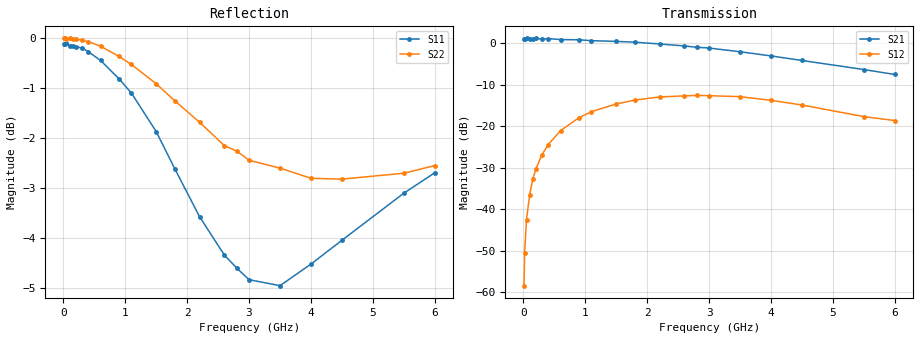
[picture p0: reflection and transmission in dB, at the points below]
! SIEMENS Small Signal Semiconductors
! BFP181
! Si NPN RF Bipolar Junction Transistor in SOT143
! VCE = 1.75 V  IC = 0.3 mA
! Common Emitter S-Parameters:  March  1996
# GHz  S  MA  R  50
!  f  S11  S21  S12  S22
! GHz  MAG  ANG  MAG  ANG  MAG  ANG  MAG  ANG
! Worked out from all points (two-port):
!   36 points, 10 MHz to 6 GHz, reference 50 ohm
!   highest |S21| = 1.19 dB at 50 MHz (marker M1); lowest = -7.5 dB at 6 GHz (marker M2)
!   |S21| within 3 dB of the highest: start of sweep to 3.373 GHz
!   lowest |S11| = -5.0 dB at 3.5 GHz (marker M3), VSWR 3.60, Z = 14.1 + j5.94 ohm
!   |S11| at or under -10 dB: nowhere
!   |S22| runs from -2.8 to 0.0 dB; largest |S21 - S12| = 1.1
!   S11 on the Smith chart (normalised r, x): 10 MHz: open; 900 MHz: 0.32, -2.40; 1.8 GHz: 0.28, -0.92; 2.8 GHz: 0.27, -0.23; 4 GHz: 0.28, +0.32; 6 GHz: 0.31, +0.98
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0.01  0.9854 -0.6  1.12 179.9  0.0012 84.2  0.9991 -0.2
0.02  0.9851 -1.2  1.13 179.7  0.003 89.5  0.999 -0.5
0.05  0.9881 -2.4  1.147 177.5  0.0075 93.8  0.9982 -1.3
0.1  0.9825 -4.9  1.119 174.8  0.0147 84.4  0.9991 -2.5
0.15  0.9828 -7.4  1.131 172.4  0.0229 84.3  0.9973 -3.7
0.2  0.9805 -9.9  1.145 169.4  0.0303 83.0  0.9973 -5.0
0.3  0.9768 -14.9  1.126 165.0  0.0454 79.3  0.9948 -7.5
0.4  0.9693 -19.7  1.138 159.0  0.06 75.2  0.9917 -9.9
0.6  0.9496 -29.5  1.11 149.0  0.0887 67.9  0.9814 -14.8
0.9  0.9103 -44.7  1.102 134.1  0.1272 56.9  0.9583 -21.9
1.1  0.8807 -54.8  1.076 124.6  0.15 50.1  0.9408 -26.4
1.5  0.8061 -75.6  1.055 106.4  0.186 36.9  0.8999 -34.9
1.8  0.74 -92.3  1.032 92.5  0.2069 28.1  0.8654 -40.6
2.2  0.6627 -115.7  0.982 75.2  0.2257 16.6  0.8236 -48.0
2.6  0.6068 -140.4  0.929 59.8  0.2325 6.4  0.7806 -54.7
2.8  0.5888 -152.4  0.896 51.5  0.2355 1.1  0.7708 -58.0
3  0.5732 -165.3  0.877 44.1  0.2337 -4.0  0.7545 -61.4
3.5  0.5653 165.3  0.791 26.8  0.2277 -14.8  0.7411 -69.7
4  0.5941 141.7  0.705 11.6  0.2055 -24.0  0.7239 -79.4
4.5  0.6276 122.7  0.621 -1.4  0.1805 -31.4  0.7225 -90.0
5.5  0.6995 97.4  0.483 -21.1  0.1308 -33.1  0.7324 -112.2
6  0.7331 88.1  0.421 -28.1  0.1173 -28.4  0.7454 -123.5
